VERSION 5.7 ;
BUSBITCHARS "[]" ;
DIVIDERCHAR "/" ;

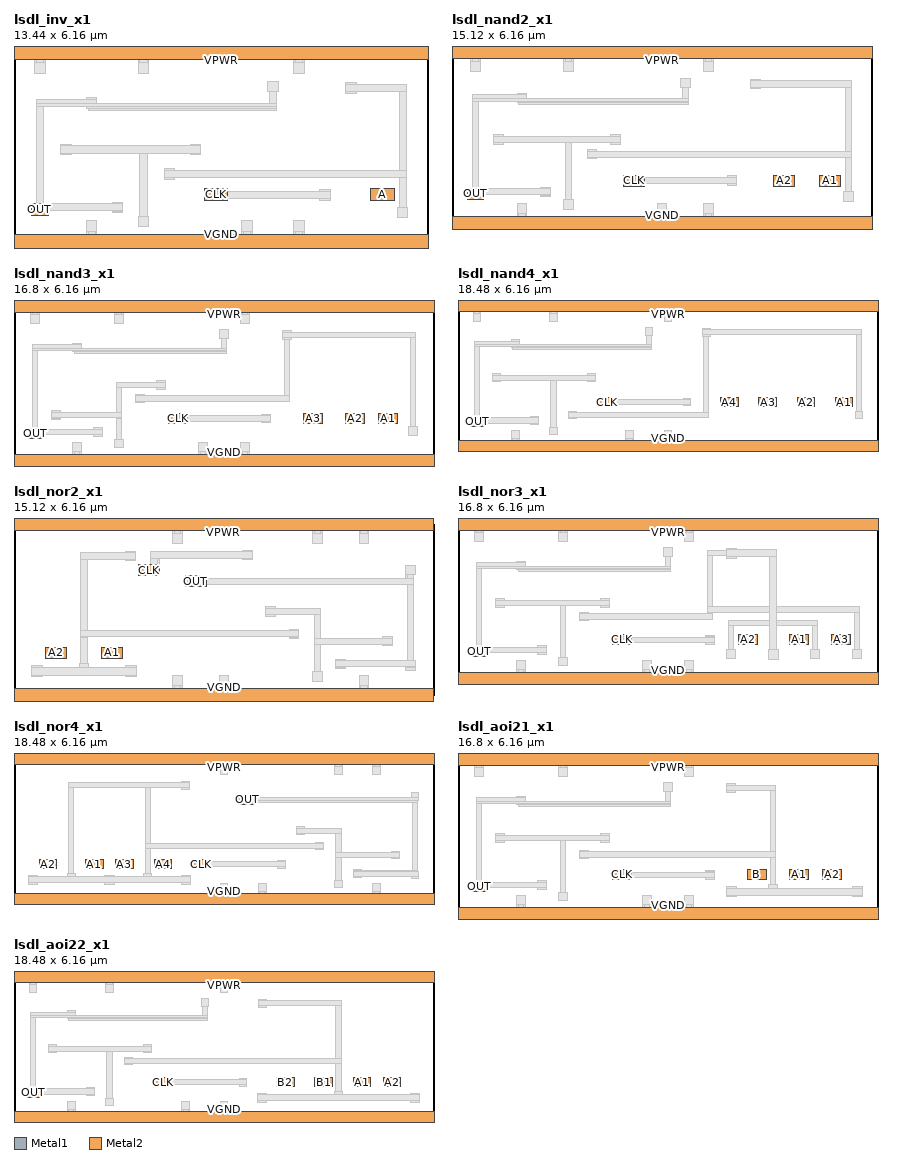
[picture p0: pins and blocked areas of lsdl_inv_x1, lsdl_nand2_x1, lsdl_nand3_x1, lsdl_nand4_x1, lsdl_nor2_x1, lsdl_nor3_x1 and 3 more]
MACRO lsdl_inv_x1
 CLASS CORE ;
 FOREIGN lsdl_inv_x1 0 0 ;
 SIZE 13.44 BY 6.16 ;
 ORIGIN 0 0 ;
 SYMMETRY X Y R90 ;
 SITE unit ;
  PIN VPWR
   DIRECTION INOUT ;
   USE POWER ;
   SHAPE ABUTMENT ;
    PORT
     CLASS CORE ;
       LAYER Metal1 ;
        RECT 0.000 5.920 13.440 6.400 ;
       LAYER Metal2 ;
        RECT 0.000 5.920 13.440 6.400 ;
    END
  END VPWR

  PIN VGND
   DIRECTION INOUT ;
   USE GROUND ;
   SHAPE ABUTMENT ;
    PORT
     CLASS CORE ;
       LAYER Metal1 ;
        RECT 0.000 -0.240 13.440 0.240 ;
       LAYER Metal2 ;
        RECT 0.000 -0.240 13.440 0.240 ;
    END
  END VGND

  PIN OUT
   DIRECTION OUTPUT ;
   USE SIGNAL ;
   SHAPE ABUTMENT ;
    PORT
     CLASS CORE ;
       LAYER Metal2 ;
        RECT 0.560 0.860 1.120 1.260 ;
    END
  END OUT

  PIN CLK
   DIRECTION INPUT ;
   ANTENNAGATEAREA 0.1 ;
   USE SIGNAL ;
   SHAPE ABUTMENT ;
    PORT
     CLASS CORE ;
       LAYER Metal2 ;
        RECT 6.160 1.330 6.920 1.725 ;
    END
  END CLK

  PIN A
   DIRECTION INPUT ;
   ANTENNAGATEAREA 0.1 ;
   USE SIGNAL ;
   SHAPE ABUTMENT ;
    PORT
     CLASS CORE ;
       LAYER Metal2 ;
        RECT 11.560 1.330 12.320 1.725 ;
    END
  END A

 OBS



    LAYER Metal1 ;
     RECT 2.350 0.240 2.405 0.350 ;
     RECT 2.635 0.240 2.690 0.350 ;
     RECT 7.390 0.240 7.445 0.350 ;
     RECT 7.675 0.240 7.730 0.350 ;
     RECT 9.070 0.240 9.125 0.350 ;
     RECT 9.355 0.240 9.410 0.350 ;
     RECT 0.670 5.810 0.725 5.920 ;
     RECT 0.955 5.810 1.010 5.920 ;
     RECT 4.030 5.810 4.085 5.920 ;
     RECT 4.315 5.810 4.370 5.920 ;
     RECT 9.070 5.810 9.125 5.920 ;
     RECT 9.355 5.810 9.410 5.920 ;
     RECT 6.520 1.330 6.920 1.410 ;
     RECT 9.910 1.360 10.250 1.410 ;
     RECT 6.520 1.415 10.250 1.640 ;
     RECT 9.910 1.645 10.250 1.695 ;
     RECT 6.520 1.645 6.920 1.725 ;
     RECT 0.640 0.860 1.040 1.005 ;
     RECT 3.190 0.955 3.530 1.005 ;
     RECT 0.640 1.010 3.530 1.235 ;
     RECT 0.640 1.240 1.040 1.260 ;
     RECT 3.190 1.240 3.530 1.290 ;
     RECT 2.405 4.250 8.515 4.330 ;
     RECT 0.725 1.260 0.955 4.385 ;
     RECT 2.350 4.330 8.515 4.385 ;
     RECT 0.725 4.385 8.515 4.475 ;
     RECT 0.725 4.480 2.690 4.615 ;
     RECT 2.350 4.615 2.690 4.670 ;
     RECT 8.285 4.480 8.515 4.865 ;
     RECT 8.230 4.870 8.570 5.205 ;
     RECT 0.670 5.470 1.010 5.810 ;
     RECT 4.030 5.470 4.370 5.810 ;
     RECT 9.070 5.470 9.410 5.810 ;
     RECT 0.725 5.810 0.955 5.920 ;
     RECT 4.085 5.810 4.315 5.920 ;
     RECT 9.125 5.810 9.355 5.920 ;
     RECT 0.000 5.920 13.440 6.400 ;
     RECT 12.430 0.790 12.770 1.130 ;
     RECT 4.870 2.035 5.210 2.085 ;
     RECT 12.485 1.130 12.715 2.085 ;
     RECT 4.870 2.090 12.715 2.315 ;
     RECT 4.870 2.320 5.210 2.370 ;
     RECT 10.750 4.830 11.090 4.885 ;
     RECT 12.485 2.320 12.715 4.885 ;
     RECT 10.750 4.885 12.715 5.115 ;
     RECT 10.750 5.115 11.090 5.170 ;
     RECT 0.000 -0.240 13.440 0.240 ;
     RECT 2.405 0.240 2.635 0.350 ;
     RECT 7.445 0.240 7.675 0.350 ;
     RECT 9.125 0.240 9.355 0.350 ;
     RECT 2.350 0.350 2.690 0.690 ;
     RECT 7.390 0.350 7.730 0.690 ;
     RECT 9.070 0.350 9.410 0.690 ;
     RECT 11.560 1.330 11.960 1.725 ;
     RECT 4.030 0.490 4.370 0.830 ;
     RECT 1.510 2.830 1.850 2.885 ;
     RECT 4.085 0.830 4.315 2.885 ;
     RECT 5.710 2.830 6.050 2.885 ;
     RECT 1.510 2.885 6.050 3.115 ;
     RECT 1.510 3.115 1.850 3.170 ;
     RECT 5.710 3.115 6.050 3.170 ;

    LAYER Via1 ;
     RECT 6.590 1.400 6.850 1.655 ;
     RECT 0.710 0.930 0.970 1.190 ;
     RECT 0.710 6.030 0.970 6.290 ;
     RECT 2.390 6.030 2.650 6.290 ;
     RECT 4.070 6.030 4.330 6.290 ;
     RECT 5.750 6.030 6.010 6.290 ;
     RECT 7.430 6.030 7.690 6.290 ;
     RECT 9.110 6.030 9.370 6.290 ;
     RECT 10.790 6.030 11.050 6.290 ;
     RECT 12.470 6.030 12.730 6.290 ;
     RECT 0.710 -0.130 0.970 0.130 ;
     RECT 2.390 -0.130 2.650 0.130 ;
     RECT 4.070 -0.130 4.330 0.130 ;
     RECT 5.750 -0.130 6.010 0.130 ;
     RECT 7.430 -0.130 7.690 0.130 ;
     RECT 9.110 -0.130 9.370 0.130 ;
     RECT 10.790 -0.130 11.050 0.130 ;
     RECT 12.470 -0.130 12.730 0.130 ;
     RECT 11.630 1.400 11.890 1.655 ;

    LAYER Metal2 ;
     RECT 6.520 1.330 6.920 1.725 ;
     RECT 0.640 0.860 1.040 1.260 ;
     RECT 0.000 5.920 13.440 6.400 ;
     RECT 0.000 -0.240 13.440 0.240 ;
     RECT 11.560 1.330 11.960 1.725 ;

 END
END lsdl_inv_x1

MACRO lsdl_nand2_x1
 CLASS CORE ;
 FOREIGN lsdl_nand2_x1 0 0 ;
 SIZE 15.120000000000001 BY 6.16 ;
 ORIGIN 0 0 ;
 SYMMETRY X Y R90 ;
 SITE unit ;
  PIN VPWR
   DIRECTION INOUT ;
   USE POWER ;
   SHAPE ABUTMENT ;
    PORT
     CLASS CORE ;
       LAYER Metal1 ;
        RECT 0.000 5.920 15.120 6.400 ;
       LAYER Metal2 ;
        RECT 0.000 5.920 15.120 6.400 ;
    END
  END VPWR

  PIN VGND
   DIRECTION INOUT ;
   USE GROUND ;
   SHAPE ABUTMENT ;
    PORT
     CLASS CORE ;
       LAYER Metal1 ;
        RECT 0.000 -0.240 15.120 0.240 ;
       LAYER Metal2 ;
        RECT 0.000 -0.240 15.120 0.240 ;
    END
  END VGND

  PIN OUT
   DIRECTION OUTPUT ;
   USE SIGNAL ;
   SHAPE ABUTMENT ;
    PORT
     CLASS CORE ;
       LAYER Metal2 ;
        RECT 0.560 0.860 1.120 1.260 ;
    END
  END OUT

  PIN CLK
   DIRECTION INPUT ;
   ANTENNAGATEAREA 0.1 ;
   USE SIGNAL ;
   SHAPE ABUTMENT ;
    PORT
     CLASS CORE ;
       LAYER Metal2 ;
        RECT 6.160 1.330 6.920 1.725 ;
    END
  END CLK

  PIN A2
   DIRECTION INPUT ;
   ANTENNAGATEAREA 0.1 ;
   USE SIGNAL ;
   SHAPE ABUTMENT ;
    PORT
     CLASS CORE ;
       LAYER Metal2 ;
        RECT 11.560 1.330 12.320 1.725 ;
    END
  END A2

  PIN A1
   DIRECTION INPUT ;
   ANTENNAGATEAREA 0.1 ;
   USE SIGNAL ;
   SHAPE ABUTMENT ;
    PORT
     CLASS CORE ;
       LAYER Metal2 ;
        RECT 13.240 1.330 14.000 1.725 ;
    END
  END A1

 OBS



    LAYER Metal1 ;
     RECT 2.350 0.240 2.405 0.350 ;
     RECT 2.635 0.240 2.690 0.350 ;
     RECT 7.390 0.240 7.445 0.350 ;
     RECT 7.675 0.240 7.730 0.350 ;
     RECT 9.070 0.240 9.125 0.350 ;
     RECT 9.355 0.240 9.410 0.350 ;
     RECT 0.670 5.810 0.725 5.920 ;
     RECT 0.955 5.810 1.010 5.920 ;
     RECT 4.030 5.810 4.085 5.920 ;
     RECT 4.315 5.810 4.370 5.920 ;
     RECT 9.070 5.810 9.125 5.920 ;
     RECT 9.355 5.810 9.410 5.920 ;
     RECT 6.520 1.330 6.920 1.410 ;
     RECT 9.910 1.360 10.250 1.410 ;
     RECT 6.520 1.415 10.250 1.640 ;
     RECT 9.910 1.645 10.250 1.695 ;
     RECT 6.520 1.645 6.920 1.725 ;
     RECT 11.560 1.330 11.960 1.725 ;
     RECT 0.640 0.860 1.040 1.005 ;
     RECT 3.190 0.955 3.530 1.005 ;
     RECT 0.640 1.010 3.530 1.235 ;
     RECT 0.640 1.240 1.040 1.260 ;
     RECT 3.190 1.240 3.530 1.290 ;
     RECT 2.405 4.250 8.515 4.330 ;
     RECT 0.725 1.260 0.955 4.385 ;
     RECT 2.350 4.330 8.515 4.385 ;
     RECT 0.725 4.385 8.515 4.475 ;
     RECT 0.725 4.480 2.690 4.615 ;
     RECT 2.350 4.615 2.690 4.670 ;
     RECT 8.285 4.480 8.515 4.865 ;
     RECT 8.230 4.870 8.570 5.205 ;
     RECT 0.670 5.470 1.010 5.810 ;
     RECT 4.030 5.470 4.370 5.810 ;
     RECT 9.070 5.470 9.410 5.810 ;
     RECT 0.725 5.810 0.955 5.920 ;
     RECT 4.085 5.810 4.315 5.920 ;
     RECT 9.125 5.810 9.355 5.920 ;
     RECT 0.000 5.920 15.120 6.400 ;
     RECT 14.110 0.790 14.450 1.130 ;
     RECT 4.870 2.305 5.210 2.355 ;
     RECT 14.165 1.130 14.395 2.355 ;
     RECT 4.870 2.360 14.395 2.585 ;
     RECT 4.870 2.590 5.210 2.640 ;
     RECT 10.750 4.830 11.090 4.885 ;
     RECT 14.165 2.590 14.395 4.885 ;
     RECT 10.750 4.885 14.395 5.115 ;
     RECT 10.750 5.115 11.090 5.170 ;
     RECT 13.240 1.330 13.640 1.725 ;
     RECT 0.000 -0.240 15.120 0.240 ;
     RECT 2.405 0.240 2.635 0.350 ;
     RECT 7.445 0.240 7.675 0.350 ;
     RECT 9.125 0.240 9.355 0.350 ;
     RECT 2.350 0.350 2.690 0.690 ;
     RECT 7.390 0.350 7.730 0.690 ;
     RECT 9.070 0.350 9.410 0.690 ;
     RECT 4.030 0.490 4.370 0.830 ;
     RECT 1.510 2.830 1.850 2.885 ;
     RECT 4.085 0.830 4.315 2.885 ;
     RECT 5.710 2.830 6.050 2.885 ;
     RECT 1.510 2.885 6.050 3.115 ;
     RECT 1.510 3.115 1.850 3.170 ;
     RECT 5.710 3.115 6.050 3.170 ;

    LAYER Via1 ;
     RECT 6.590 1.400 6.850 1.655 ;
     RECT 11.630 1.400 11.890 1.655 ;
     RECT 0.710 0.930 0.970 1.190 ;
     RECT 0.710 6.030 0.970 6.290 ;
     RECT 2.390 6.030 2.650 6.290 ;
     RECT 4.070 6.030 4.330 6.290 ;
     RECT 5.750 6.030 6.010 6.290 ;
     RECT 7.430 6.030 7.690 6.290 ;
     RECT 9.110 6.030 9.370 6.290 ;
     RECT 10.790 6.030 11.050 6.290 ;
     RECT 12.470 6.030 12.730 6.290 ;
     RECT 14.150 6.030 14.410 6.290 ;
     RECT 13.310 1.400 13.570 1.655 ;
     RECT 0.710 -0.130 0.970 0.130 ;
     RECT 2.390 -0.130 2.650 0.130 ;
     RECT 4.070 -0.130 4.330 0.130 ;
     RECT 5.750 -0.130 6.010 0.130 ;
     RECT 7.430 -0.130 7.690 0.130 ;
     RECT 9.110 -0.130 9.370 0.130 ;
     RECT 10.790 -0.130 11.050 0.130 ;
     RECT 12.470 -0.130 12.730 0.130 ;
     RECT 14.150 -0.130 14.410 0.130 ;

    LAYER Metal2 ;
     RECT 6.520 1.330 6.920 1.725 ;
     RECT 11.560 1.330 11.960 1.725 ;
     RECT 0.640 0.860 1.040 1.260 ;
     RECT 0.000 5.920 15.120 6.400 ;
     RECT 13.240 1.330 13.640 1.725 ;
     RECT 0.000 -0.240 15.120 0.240 ;

 END
END lsdl_nand2_x1

MACRO lsdl_nand3_x1
 CLASS CORE ;
 FOREIGN lsdl_nand3_x1 0 0 ;
 SIZE 16.8 BY 6.16 ;
 ORIGIN 0 0 ;
 SYMMETRY X Y R90 ;
 SITE unit ;
  PIN VPWR
   DIRECTION INOUT ;
   USE POWER ;
   SHAPE ABUTMENT ;
    PORT
     CLASS CORE ;
       LAYER Metal1 ;
        RECT 0.000 5.920 16.800 6.400 ;
       LAYER Metal2 ;
        RECT 0.000 5.920 16.800 6.400 ;
    END
  END VPWR

  PIN VGND
   DIRECTION INOUT ;
   USE GROUND ;
   SHAPE ABUTMENT ;
    PORT
     CLASS CORE ;
       LAYER Metal1 ;
        RECT 0.000 -0.240 16.800 0.240 ;
       LAYER Metal2 ;
        RECT 0.000 -0.240 16.800 0.240 ;
    END
  END VGND

  PIN OUT
   DIRECTION OUTPUT ;
   USE SIGNAL ;
   SHAPE ABUTMENT ;
    PORT
     CLASS CORE ;
       LAYER Metal2 ;
        RECT 0.560 0.860 1.120 1.260 ;
    END
  END OUT

  PIN CLK
   DIRECTION INPUT ;
   ANTENNAGATEAREA 0.1 ;
   USE SIGNAL ;
   SHAPE ABUTMENT ;
    PORT
     CLASS CORE ;
       LAYER Metal2 ;
        RECT 6.160 1.465 6.920 1.860 ;
    END
  END CLK

  PIN A1
   DIRECTION INPUT ;
   ANTENNAGATEAREA 0.1 ;
   USE SIGNAL ;
   SHAPE ABUTMENT ;
    PORT
     CLASS CORE ;
       LAYER Metal2 ;
        RECT 14.560 1.465 15.320 1.860 ;
    END
  END A1

  PIN A3
   DIRECTION INPUT ;
   ANTENNAGATEAREA 0.1 ;
   USE SIGNAL ;
   SHAPE ABUTMENT ;
    PORT
     CLASS CORE ;
       LAYER Metal2 ;
        RECT 11.560 1.465 12.320 1.860 ;
    END
  END A3

  PIN A2
   DIRECTION INPUT ;
   ANTENNAGATEAREA 0.1 ;
   USE SIGNAL ;
   SHAPE ABUTMENT ;
    PORT
     CLASS CORE ;
       LAYER Metal2 ;
        RECT 13.240 1.465 14.000 1.860 ;
    END
  END A2

 OBS



    LAYER Metal1 ;
     RECT 2.350 0.240 2.405 0.350 ;
     RECT 2.635 0.240 2.690 0.350 ;
     RECT 7.390 0.240 7.445 0.350 ;
     RECT 7.675 0.240 7.730 0.350 ;
     RECT 9.070 0.240 9.125 0.350 ;
     RECT 9.355 0.240 9.410 0.350 ;
     RECT 0.670 5.810 0.725 5.920 ;
     RECT 0.955 5.810 1.010 5.920 ;
     RECT 4.030 5.810 4.085 5.920 ;
     RECT 4.315 5.810 4.370 5.920 ;
     RECT 9.070 5.810 9.125 5.920 ;
     RECT 9.355 5.810 9.410 5.920 ;
     RECT 6.520 1.465 6.920 1.545 ;
     RECT 9.910 1.495 10.250 1.545 ;
     RECT 6.520 1.550 10.250 1.775 ;
     RECT 9.910 1.780 10.250 1.830 ;
     RECT 6.520 1.780 6.920 1.860 ;
     RECT 13.240 1.465 13.640 1.860 ;
     RECT 0.640 0.860 1.040 1.005 ;
     RECT 3.190 0.955 3.530 1.005 ;
     RECT 0.640 1.010 3.530 1.235 ;
     RECT 0.640 1.240 1.040 1.260 ;
     RECT 3.190 1.240 3.530 1.290 ;
     RECT 2.405 4.250 8.515 4.330 ;
     RECT 0.725 1.260 0.955 4.385 ;
     RECT 2.350 4.330 8.515 4.385 ;
     RECT 0.725 4.385 8.515 4.475 ;
     RECT 0.725 4.480 2.690 4.615 ;
     RECT 2.350 4.615 2.690 4.670 ;
     RECT 8.285 4.480 8.515 4.865 ;
     RECT 8.230 4.870 8.570 5.205 ;
     RECT 0.670 5.470 1.010 5.810 ;
     RECT 4.030 5.470 4.370 5.810 ;
     RECT 9.070 5.470 9.410 5.810 ;
     RECT 0.725 5.810 0.955 5.920 ;
     RECT 4.085 5.810 4.315 5.920 ;
     RECT 9.125 5.810 9.355 5.920 ;
     RECT 0.000 5.920 16.800 6.400 ;
     RECT 15.790 0.990 16.130 1.330 ;
     RECT 4.870 2.305 5.210 2.355 ;
     RECT 4.870 2.360 11.035 2.585 ;
     RECT 4.870 2.590 5.210 2.640 ;
     RECT 10.805 2.590 11.035 4.830 ;
     RECT 10.750 4.830 11.090 4.885 ;
     RECT 15.845 1.330 16.075 4.885 ;
     RECT 10.750 4.885 16.075 5.115 ;
     RECT 10.750 5.115 11.090 5.170 ;
     RECT 14.920 1.465 15.320 1.860 ;
     RECT 0.000 -0.240 16.800 0.240 ;
     RECT 2.405 0.240 2.635 0.350 ;
     RECT 7.445 0.240 7.675 0.350 ;
     RECT 9.125 0.240 9.355 0.350 ;
     RECT 2.350 0.350 2.690 0.690 ;
     RECT 7.390 0.350 7.730 0.690 ;
     RECT 9.070 0.350 9.410 0.690 ;
     RECT 11.560 1.465 11.960 1.860 ;
     RECT 4.030 0.490 4.370 0.830 ;
     RECT 1.510 1.630 1.850 1.680 ;
     RECT 4.085 0.830 4.315 1.680 ;
     RECT 1.510 1.685 4.315 1.910 ;
     RECT 1.510 1.915 1.850 1.965 ;
     RECT 4.085 1.915 4.315 2.885 ;
     RECT 5.710 2.830 6.050 2.885 ;
     RECT 4.085 2.885 6.050 3.115 ;
     RECT 5.710 3.115 6.050 3.170 ;

    LAYER Via1 ;
     RECT 6.590 1.535 6.850 1.790 ;
     RECT 13.310 1.535 13.570 1.790 ;
     RECT 0.710 0.930 0.970 1.190 ;
     RECT 0.710 6.030 0.970 6.290 ;
     RECT 2.390 6.030 2.650 6.290 ;
     RECT 4.070 6.030 4.330 6.290 ;
     RECT 5.750 6.030 6.010 6.290 ;
     RECT 7.430 6.030 7.690 6.290 ;
     RECT 9.110 6.030 9.370 6.290 ;
     RECT 10.790 6.030 11.050 6.290 ;
     RECT 12.470 6.030 12.730 6.290 ;
     RECT 14.150 6.030 14.410 6.290 ;
     RECT 15.830 6.030 16.090 6.290 ;
     RECT 14.990 1.535 15.250 1.790 ;
     RECT 0.710 -0.130 0.970 0.130 ;
     RECT 2.390 -0.130 2.650 0.130 ;
     RECT 4.070 -0.130 4.330 0.130 ;
     RECT 5.750 -0.130 6.010 0.130 ;
     RECT 7.430 -0.130 7.690 0.130 ;
     RECT 9.110 -0.130 9.370 0.130 ;
     RECT 10.790 -0.130 11.050 0.130 ;
     RECT 12.470 -0.130 12.730 0.130 ;
     RECT 14.150 -0.130 14.410 0.130 ;
     RECT 15.830 -0.130 16.090 0.130 ;
     RECT 11.630 1.535 11.890 1.790 ;

    LAYER Metal2 ;
     RECT 6.520 1.465 6.920 1.860 ;
     RECT 13.240 1.465 13.640 1.860 ;
     RECT 0.640 0.860 1.040 1.260 ;
     RECT 0.000 5.920 16.800 6.400 ;
     RECT 14.920 1.465 15.320 1.860 ;
     RECT 0.000 -0.240 16.800 0.240 ;
     RECT 11.560 1.465 11.960 1.860 ;

 END
END lsdl_nand3_x1

MACRO lsdl_nand4_x1
 CLASS CORE ;
 FOREIGN lsdl_nand4_x1 0 0 ;
 SIZE 18.48 BY 6.16 ;
 ORIGIN 0 0 ;
 SYMMETRY X Y R90 ;
 SITE unit ;
  PIN VPWR
   DIRECTION INOUT ;
   USE POWER ;
   SHAPE ABUTMENT ;
    PORT
     CLASS CORE ;
       LAYER Metal1 ;
        RECT 0.000 5.920 18.480 6.400 ;
       LAYER Metal2 ;
        RECT 0.000 5.920 18.480 6.400 ;
    END
  END VPWR

  PIN VGND
   DIRECTION INOUT ;
   USE GROUND ;
   SHAPE ABUTMENT ;
    PORT
     CLASS CORE ;
       LAYER Metal1 ;
        RECT 0.000 -0.240 18.480 0.240 ;
       LAYER Metal2 ;
        RECT 0.000 -0.240 18.480 0.240 ;
    END
  END VGND

  PIN OUT
   DIRECTION OUTPUT ;
   USE SIGNAL ;
   SHAPE ABUTMENT ;
    PORT
     CLASS CORE ;
       LAYER Metal2 ;
        RECT 0.560 0.860 1.120 1.260 ;
    END
  END OUT

  PIN A4
   DIRECTION INPUT ;
   ANTENNAGATEAREA 0.1 ;
   USE SIGNAL ;
   SHAPE ABUTMENT ;
    PORT
     CLASS CORE ;
       LAYER Metal2 ;
        RECT 11.560 1.735 12.320 2.130 ;
    END
  END A4

  PIN A2
   DIRECTION INPUT ;
   ANTENNAGATEAREA 0.1 ;
   USE SIGNAL ;
   SHAPE ABUTMENT ;
    PORT
     CLASS CORE ;
       LAYER Metal2 ;
        RECT 14.920 1.735 15.680 2.130 ;
    END
  END A2

  PIN CLK
   DIRECTION INPUT ;
   ANTENNAGATEAREA 0.1 ;
   USE SIGNAL ;
   SHAPE ABUTMENT ;
    PORT
     CLASS CORE ;
       LAYER Metal2 ;
        RECT 6.160 1.735 6.920 2.130 ;
    END
  END CLK

  PIN A1
   DIRECTION INPUT ;
   ANTENNAGATEAREA 0.1 ;
   USE SIGNAL ;
   SHAPE ABUTMENT ;
    PORT
     CLASS CORE ;
       LAYER Metal2 ;
        RECT 16.600 1.735 17.360 2.130 ;
    END
  END A1

  PIN A3
   DIRECTION INPUT ;
   ANTENNAGATEAREA 0.1 ;
   USE SIGNAL ;
   SHAPE ABUTMENT ;
    PORT
     CLASS CORE ;
       LAYER Metal2 ;
        RECT 13.240 1.735 14.000 2.130 ;
    END
  END A3

 OBS



    LAYER Metal1 ;
     RECT 2.350 0.240 2.405 0.350 ;
     RECT 2.635 0.240 2.690 0.350 ;
     RECT 7.390 0.240 7.445 0.350 ;
     RECT 7.675 0.240 7.730 0.350 ;
     RECT 9.070 0.240 9.125 0.350 ;
     RECT 9.355 0.240 9.410 0.350 ;
     RECT 0.670 5.810 0.725 5.920 ;
     RECT 0.955 5.810 1.010 5.920 ;
     RECT 4.030 5.810 4.085 5.920 ;
     RECT 4.315 5.810 4.370 5.920 ;
     RECT 9.070 5.810 9.125 5.920 ;
     RECT 9.355 5.810 9.410 5.920 ;
     RECT 6.520 1.735 6.920 1.815 ;
     RECT 9.910 1.765 10.250 1.815 ;
     RECT 6.520 1.820 10.250 2.045 ;
     RECT 9.910 2.050 10.250 2.100 ;
     RECT 6.520 2.050 6.920 2.130 ;
     RECT 14.920 1.735 15.320 2.130 ;
     RECT 0.640 0.860 1.040 1.005 ;
     RECT 3.190 0.955 3.530 1.005 ;
     RECT 0.640 1.010 3.530 1.235 ;
     RECT 0.640 1.240 1.040 1.260 ;
     RECT 3.190 1.240 3.530 1.290 ;
     RECT 2.405 4.250 8.515 4.330 ;
     RECT 0.725 1.260 0.955 4.385 ;
     RECT 2.350 4.330 8.515 4.385 ;
     RECT 0.725 4.385 8.515 4.475 ;
     RECT 0.725 4.480 2.690 4.615 ;
     RECT 2.350 4.615 2.690 4.670 ;
     RECT 8.285 4.480 8.515 4.865 ;
     RECT 8.230 4.870 8.570 5.205 ;
     RECT 0.670 5.470 1.010 5.810 ;
     RECT 4.030 5.470 4.370 5.810 ;
     RECT 9.070 5.470 9.410 5.810 ;
     RECT 0.725 5.810 0.955 5.920 ;
     RECT 4.085 5.810 4.315 5.920 ;
     RECT 9.125 5.810 9.355 5.920 ;
     RECT 0.000 5.920 18.480 6.400 ;
     RECT 4.870 1.190 5.210 1.245 ;
     RECT 4.870 1.245 11.035 1.475 ;
     RECT 4.870 1.475 5.210 1.530 ;
     RECT 17.470 1.190 17.810 1.530 ;
     RECT 10.805 1.475 11.035 4.830 ;
     RECT 10.750 4.830 11.090 4.885 ;
     RECT 17.525 1.530 17.755 4.885 ;
     RECT 10.750 4.885 17.755 5.115 ;
     RECT 10.750 5.115 11.090 5.170 ;
     RECT 16.600 1.735 17.000 2.130 ;
     RECT 0.000 -0.240 18.480 0.240 ;
     RECT 2.405 0.240 2.635 0.350 ;
     RECT 7.445 0.240 7.675 0.350 ;
     RECT 9.125 0.240 9.355 0.350 ;
     RECT 2.350 0.350 2.690 0.690 ;
     RECT 7.390 0.350 7.730 0.690 ;
     RECT 9.070 0.350 9.410 0.690 ;
     RECT 11.560 1.735 11.960 2.130 ;
     RECT 13.240 1.735 13.640 2.130 ;
     RECT 4.030 0.490 4.370 0.830 ;
     RECT 1.510 2.830 1.850 2.885 ;
     RECT 4.085 0.830 4.315 2.885 ;
     RECT 5.710 2.830 6.050 2.885 ;
     RECT 1.510 2.885 6.050 3.115 ;
     RECT 1.510 3.115 1.850 3.170 ;
     RECT 5.710 3.115 6.050 3.170 ;

    LAYER Via1 ;
     RECT 6.590 1.805 6.850 2.060 ;
     RECT 14.990 1.805 15.250 2.060 ;
     RECT 0.710 0.930 0.970 1.190 ;
     RECT 0.710 6.030 0.970 6.290 ;
     RECT 2.390 6.030 2.650 6.290 ;
     RECT 4.070 6.030 4.330 6.290 ;
     RECT 5.750 6.030 6.010 6.290 ;
     RECT 7.430 6.030 7.690 6.290 ;
     RECT 9.110 6.030 9.370 6.290 ;
     RECT 10.790 6.030 11.050 6.290 ;
     RECT 12.470 6.030 12.730 6.290 ;
     RECT 14.150 6.030 14.410 6.290 ;
     RECT 15.830 6.030 16.090 6.290 ;
     RECT 17.510 6.030 17.770 6.290 ;
     RECT 16.670 1.805 16.930 2.060 ;
     RECT 0.710 -0.130 0.970 0.130 ;
     RECT 2.390 -0.130 2.650 0.130 ;
     RECT 4.070 -0.130 4.330 0.130 ;
     RECT 5.750 -0.130 6.010 0.130 ;
     RECT 7.430 -0.130 7.690 0.130 ;
     RECT 9.110 -0.130 9.370 0.130 ;
     RECT 10.790 -0.130 11.050 0.130 ;
     RECT 12.470 -0.130 12.730 0.130 ;
     RECT 14.150 -0.130 14.410 0.130 ;
     RECT 15.830 -0.130 16.090 0.130 ;
     RECT 17.510 -0.130 17.770 0.130 ;
     RECT 11.630 1.805 11.890 2.060 ;
     RECT 13.310 1.805 13.570 2.060 ;

    LAYER Metal2 ;
     RECT 6.520 1.735 6.920 2.130 ;
     RECT 14.920 1.735 15.320 2.130 ;
     RECT 0.640 0.860 1.040 1.260 ;
     RECT 0.000 5.920 18.480 6.400 ;
     RECT 16.600 1.735 17.000 2.130 ;
     RECT 0.000 -0.240 18.480 0.240 ;
     RECT 11.560 1.735 11.960 2.130 ;
     RECT 13.240 1.735 13.640 2.130 ;

 END
END lsdl_nand4_x1

MACRO lsdl_nor2_x1
 CLASS CORE ;
 FOREIGN lsdl_nor2_x1 0 0 ;
 SIZE 15.120000000000001 BY 6.16 ;
 ORIGIN 0 0 ;
 SYMMETRY X Y R90 ;
 SITE unit ;
  PIN VPWR
   DIRECTION INOUT ;
   USE POWER ;
   SHAPE ABUTMENT ;
    PORT
     CLASS CORE ;
       LAYER Metal1 ;
        RECT 0.000 5.920 15.120 6.400 ;
       LAYER Metal2 ;
        RECT 0.000 5.920 15.120 6.400 ;
    END
  END VPWR

  PIN VGND
   DIRECTION INOUT ;
   USE GROUND ;
   SHAPE ABUTMENT ;
    PORT
     CLASS CORE ;
       LAYER Metal1 ;
        RECT 0.000 -0.240 15.120 0.240 ;
       LAYER Metal2 ;
        RECT 0.000 -0.240 15.120 0.240 ;
    END
  END VGND

  PIN OUT
   DIRECTION OUTPUT ;
   USE SIGNAL ;
   SHAPE ABUTMENT ;
    PORT
     CLASS CORE ;
       LAYER Metal2 ;
        RECT 6.160 3.895 6.920 4.290 ;
    END
  END OUT

  PIN A1
   DIRECTION INPUT ;
   ANTENNAGATEAREA 0.1 ;
   USE SIGNAL ;
   SHAPE ABUTMENT ;
    PORT
     CLASS CORE ;
       LAYER Metal2 ;
        RECT 3.160 1.330 3.920 1.725 ;
    END
  END A1

  PIN CLK
   DIRECTION INPUT ;
   ANTENNAGATEAREA 0.1 ;
   USE SIGNAL ;
   SHAPE ABUTMENT ;
    PORT
     CLASS CORE ;
       LAYER Metal2 ;
        RECT 4.480 4.300 5.240 4.700 ;
    END
  END CLK

  PIN A2
   DIRECTION INPUT ;
   ANTENNAGATEAREA 0.1 ;
   USE SIGNAL ;
   SHAPE ABUTMENT ;
    PORT
     CLASS CORE ;
       LAYER Metal2 ;
        RECT 1.120 1.330 1.880 1.725 ;
    END
  END A2

 OBS



    LAYER Metal1 ;
     RECT 5.710 0.240 5.765 0.350 ;
     RECT 5.995 0.240 6.050 0.350 ;
     RECT 7.390 0.240 7.445 0.350 ;
     RECT 7.675 0.240 7.730 0.350 ;
     RECT 12.430 0.240 12.485 0.350 ;
     RECT 12.715 0.240 12.770 0.350 ;
     RECT 14.110 4.210 14.165 4.330 ;
     RECT 5.155 4.700 5.240 4.920 ;
     RECT 5.710 5.810 5.765 5.920 ;
     RECT 5.995 5.810 6.050 5.920 ;
     RECT 10.750 5.810 10.805 5.920 ;
     RECT 11.035 5.810 11.090 5.920 ;
     RECT 12.430 5.810 12.485 5.920 ;
     RECT 12.715 5.810 12.770 5.920 ;
     RECT 4.840 4.300 5.240 4.700 ;
     RECT 4.925 4.700 5.155 4.920 ;
     RECT 8.230 4.870 8.570 4.920 ;
     RECT 4.925 4.925 8.570 5.150 ;
     RECT 8.230 5.155 8.570 5.205 ;
     RECT 1.480 1.330 1.880 1.725 ;
     RECT 11.590 0.955 11.930 1.005 ;
     RECT 14.110 0.890 14.450 1.005 ;
     RECT 11.590 1.010 14.450 1.230 ;
     RECT 11.590 1.230 14.395 1.235 ;
     RECT 11.590 1.240 11.930 1.290 ;
     RECT 6.520 3.895 6.920 3.975 ;
     RECT 14.165 1.240 14.395 3.975 ;
     RECT 6.520 3.980 14.395 4.205 ;
     RECT 6.520 4.210 6.920 4.290 ;
     RECT 14.165 4.210 14.395 4.330 ;
     RECT 14.110 4.330 14.450 4.670 ;
     RECT 5.710 5.470 6.050 5.810 ;
     RECT 10.750 5.470 11.090 5.810 ;
     RECT 12.430 5.470 12.770 5.810 ;
     RECT 5.765 5.810 5.995 5.920 ;
     RECT 10.805 5.810 11.035 5.920 ;
     RECT 12.485 5.810 12.715 5.920 ;
     RECT 0.000 5.920 15.120 6.400 ;
     RECT 2.350 0.790 2.690 1.130 ;
     RECT 2.405 1.130 2.635 2.085 ;
     RECT 9.910 2.035 10.250 2.085 ;
     RECT 2.405 2.090 10.250 2.315 ;
     RECT 9.910 2.320 10.250 2.370 ;
     RECT 2.405 2.320 2.635 4.885 ;
     RECT 4.030 4.830 4.370 4.885 ;
     RECT 2.405 4.885 4.370 5.115 ;
     RECT 4.030 5.115 4.370 5.170 ;
     RECT 3.160 1.330 3.560 1.725 ;
     RECT 0.640 0.655 1.040 1.050 ;
     RECT 4.000 0.655 4.400 1.050 ;
     RECT 0.000 -0.240 15.120 0.240 ;
     RECT 5.765 0.240 5.995 0.350 ;
     RECT 7.445 0.240 7.675 0.350 ;
     RECT 12.485 0.240 12.715 0.350 ;
     RECT 5.710 0.350 6.050 0.690 ;
     RECT 7.390 0.350 7.730 0.690 ;
     RECT 12.430 0.350 12.770 0.690 ;
     RECT 10.750 0.490 11.090 0.830 ;
     RECT 10.805 0.830 11.035 1.815 ;
     RECT 13.270 1.765 13.610 1.815 ;
     RECT 10.805 1.820 13.610 2.045 ;
     RECT 13.270 2.050 13.610 2.100 ;
     RECT 9.070 2.830 9.410 2.885 ;
     RECT 10.805 2.050 11.035 2.885 ;
     RECT 9.070 2.885 11.035 3.115 ;
     RECT 9.070 3.115 9.410 3.170 ;

    LAYER Via1 ;
     RECT 4.910 4.370 5.170 4.630 ;
     RECT 1.550 1.400 1.810 1.655 ;
     RECT 6.590 3.965 6.850 4.220 ;
     RECT 0.710 6.030 0.970 6.290 ;
     RECT 2.390 6.030 2.650 6.290 ;
     RECT 4.070 6.030 4.330 6.290 ;
     RECT 5.750 6.030 6.010 6.290 ;
     RECT 7.430 6.030 7.690 6.290 ;
     RECT 9.110 6.030 9.370 6.290 ;
     RECT 10.790 6.030 11.050 6.290 ;
     RECT 12.470 6.030 12.730 6.290 ;
     RECT 14.150 6.030 14.410 6.290 ;
     RECT 3.230 1.400 3.490 1.655 ;
     RECT 0.710 0.725 0.970 0.980 ;
     RECT 4.070 0.725 4.330 0.980 ;
     RECT 0.710 -0.130 0.970 0.130 ;
     RECT 2.390 -0.130 2.650 0.130 ;
     RECT 4.070 -0.130 4.330 0.130 ;
     RECT 5.750 -0.130 6.010 0.130 ;
     RECT 7.430 -0.130 7.690 0.130 ;
     RECT 9.110 -0.130 9.370 0.130 ;
     RECT 10.790 -0.130 11.050 0.130 ;
     RECT 12.470 -0.130 12.730 0.130 ;
     RECT 14.150 -0.130 14.410 0.130 ;

    LAYER Metal2 ;
     RECT 4.840 4.300 5.240 4.700 ;
     RECT 1.480 1.330 1.880 1.725 ;
     RECT 6.520 3.895 6.920 4.290 ;
     RECT 0.000 5.920 15.120 6.400 ;
     RECT 3.160 1.330 3.560 1.725 ;
     RECT 0.640 0.655 1.040 0.710 ;
     RECT 4.000 0.655 4.400 0.710 ;
     RECT 0.640 0.715 4.400 0.990 ;
     RECT 0.640 0.995 1.040 1.050 ;
     RECT 4.000 0.995 4.400 1.050 ;
     RECT 0.000 -0.240 15.120 0.240 ;

 END
END lsdl_nor2_x1

MACRO lsdl_nor3_x1
 CLASS CORE ;
 FOREIGN lsdl_nor3_x1 0 0 ;
 SIZE 16.8 BY 6.16 ;
 ORIGIN 0 0 ;
 SYMMETRY X Y R90 ;
 SITE unit ;
  PIN VPWR
   DIRECTION INOUT ;
   USE POWER ;
   SHAPE ABUTMENT ;
    PORT
     CLASS CORE ;
       LAYER Metal1 ;
        RECT 0.000 5.920 16.800 6.400 ;
       LAYER Metal2 ;
        RECT 0.000 5.920 16.800 6.400 ;
    END
  END VPWR

  PIN VGND
   DIRECTION INOUT ;
   USE GROUND ;
   SHAPE ABUTMENT ;
    PORT
     CLASS CORE ;
       LAYER Metal1 ;
        RECT 0.000 -0.240 16.800 0.240 ;
       LAYER Metal2 ;
        RECT 0.000 -0.240 16.800 0.240 ;
    END
  END VGND

  PIN OUT
   DIRECTION OUTPUT ;
   USE SIGNAL ;
   SHAPE ABUTMENT ;
    PORT
     CLASS CORE ;
       LAYER Metal2 ;
        RECT 0.560 0.860 1.120 1.260 ;
    END
  END OUT

  PIN A2
   DIRECTION INPUT ;
   ANTENNAGATEAREA 0.1 ;
   USE SIGNAL ;
   SHAPE ABUTMENT ;
    PORT
     CLASS CORE ;
       LAYER Metal2 ;
        RECT 11.200 1.330 11.960 1.725 ;
    END
  END A2

  PIN A3
   DIRECTION INPUT ;
   ANTENNAGATEAREA 0.1 ;
   USE SIGNAL ;
   SHAPE ABUTMENT ;
    PORT
     CLASS CORE ;
       LAYER Metal2 ;
        RECT 14.920 1.330 15.680 1.725 ;
    END
  END A3

  PIN CLK
   DIRECTION INPUT ;
   ANTENNAGATEAREA 0.1 ;
   USE SIGNAL ;
   SHAPE ABUTMENT ;
    PORT
     CLASS CORE ;
       LAYER Metal2 ;
        RECT 6.160 1.330 6.920 1.725 ;
    END
  END CLK

  PIN A1
   DIRECTION INPUT ;
   ANTENNAGATEAREA 0.1 ;
   USE SIGNAL ;
   SHAPE ABUTMENT ;
    PORT
     CLASS CORE ;
       LAYER Metal2 ;
        RECT 13.240 1.330 14.000 1.725 ;
    END
  END A1

 OBS



    LAYER Metal1 ;
     RECT 2.350 0.240 2.405 0.350 ;
     RECT 2.635 0.240 2.690 0.350 ;
     RECT 7.390 0.240 7.445 0.350 ;
     RECT 7.675 0.240 7.730 0.350 ;
     RECT 9.070 0.240 9.125 0.350 ;
     RECT 9.355 0.240 9.410 0.350 ;
     RECT 0.670 5.810 0.725 5.920 ;
     RECT 0.955 5.810 1.010 5.920 ;
     RECT 4.030 5.810 4.085 5.920 ;
     RECT 4.315 5.810 4.370 5.920 ;
     RECT 9.070 5.810 9.125 5.920 ;
     RECT 9.355 5.810 9.410 5.920 ;
     RECT 6.520 1.330 6.920 1.410 ;
     RECT 9.910 1.360 10.250 1.410 ;
     RECT 6.520 1.415 10.250 1.640 ;
     RECT 9.910 1.645 10.250 1.695 ;
     RECT 6.520 1.645 6.920 1.725 ;
     RECT 11.560 1.330 11.960 1.725 ;
     RECT 0.640 0.860 1.040 1.005 ;
     RECT 3.190 0.955 3.530 1.005 ;
     RECT 0.640 1.010 3.530 1.235 ;
     RECT 0.640 1.240 1.040 1.260 ;
     RECT 3.190 1.240 3.530 1.290 ;
     RECT 2.405 4.250 8.515 4.330 ;
     RECT 0.725 1.260 0.955 4.385 ;
     RECT 2.350 4.330 8.515 4.385 ;
     RECT 0.725 4.385 8.515 4.475 ;
     RECT 0.725 4.480 2.690 4.615 ;
     RECT 2.350 4.615 2.690 4.670 ;
     RECT 8.285 4.480 8.515 4.865 ;
     RECT 8.230 4.870 8.570 5.205 ;
     RECT 0.670 5.470 1.010 5.810 ;
     RECT 4.030 5.470 4.370 5.810 ;
     RECT 9.070 5.470 9.410 5.810 ;
     RECT 0.725 5.810 0.955 5.920 ;
     RECT 4.085 5.810 4.315 5.920 ;
     RECT 9.125 5.810 9.355 5.920 ;
     RECT 0.000 5.920 16.800 6.400 ;
     RECT 12.400 0.760 12.800 1.160 ;
     RECT 15.790 0.790 16.130 1.130 ;
     RECT 4.870 2.305 5.210 2.355 ;
     RECT 4.870 2.360 10.195 2.585 ;
     RECT 9.965 2.590 10.195 2.625 ;
     RECT 15.845 1.130 16.075 2.625 ;
     RECT 4.870 2.590 5.210 2.640 ;
     RECT 9.965 2.630 16.075 2.855 ;
     RECT 9.965 2.860 10.195 4.885 ;
     RECT 10.720 4.800 11.120 4.885 ;
     RECT 9.965 4.885 11.120 5.115 ;
     RECT 10.720 5.115 11.120 5.200 ;
     RECT 13.240 1.330 13.640 1.725 ;
     RECT 10.750 0.790 11.090 1.130 ;
     RECT 14.110 0.790 14.450 1.130 ;
     RECT 10.805 1.130 11.035 2.085 ;
     RECT 14.165 1.130 14.395 2.085 ;
     RECT 10.805 2.090 14.395 2.315 ;
     RECT 0.000 -0.240 16.800 0.240 ;
     RECT 2.405 0.240 2.635 0.350 ;
     RECT 7.445 0.240 7.675 0.350 ;
     RECT 9.125 0.240 9.355 0.350 ;
     RECT 2.350 0.350 2.690 0.690 ;
     RECT 7.390 0.350 7.730 0.690 ;
     RECT 9.070 0.350 9.410 0.690 ;
     RECT 14.920 1.330 15.320 1.725 ;
     RECT 4.030 0.490 4.370 0.830 ;
     RECT 1.510 2.830 1.850 2.885 ;
     RECT 4.085 0.830 4.315 2.885 ;
     RECT 5.710 2.830 6.050 2.885 ;
     RECT 1.510 2.885 6.050 3.115 ;
     RECT 1.510 3.115 1.850 3.170 ;
     RECT 5.710 3.115 6.050 3.170 ;

    LAYER Via1 ;
     RECT 6.590 1.400 6.850 1.655 ;
     RECT 11.630 1.400 11.890 1.655 ;
     RECT 0.710 0.930 0.970 1.190 ;
     RECT 0.710 6.030 0.970 6.290 ;
     RECT 2.390 6.030 2.650 6.290 ;
     RECT 4.070 6.030 4.330 6.290 ;
     RECT 5.750 6.030 6.010 6.290 ;
     RECT 7.430 6.030 7.690 6.290 ;
     RECT 9.110 6.030 9.370 6.290 ;
     RECT 10.790 6.030 11.050 6.290 ;
     RECT 12.470 6.030 12.730 6.290 ;
     RECT 14.150 6.030 14.410 6.290 ;
     RECT 15.830 6.030 16.090 6.290 ;
     RECT 12.470 0.830 12.730 1.090 ;
     RECT 10.790 4.870 11.050 5.130 ;
     RECT 13.310 1.400 13.570 1.655 ;
     RECT 0.710 -0.130 0.970 0.130 ;
     RECT 2.390 -0.130 2.650 0.130 ;
     RECT 4.070 -0.130 4.330 0.130 ;
     RECT 5.750 -0.130 6.010 0.130 ;
     RECT 7.430 -0.130 7.690 0.130 ;
     RECT 9.110 -0.130 9.370 0.130 ;
     RECT 10.790 -0.130 11.050 0.130 ;
     RECT 12.470 -0.130 12.730 0.130 ;
     RECT 14.150 -0.130 14.410 0.130 ;
     RECT 15.830 -0.130 16.090 0.130 ;
     RECT 14.990 1.400 15.250 1.655 ;

    LAYER Metal2 ;
     RECT 6.520 1.330 6.920 1.725 ;
     RECT 11.560 1.330 11.960 1.725 ;
     RECT 0.640 0.860 1.040 1.260 ;
     RECT 0.000 5.920 16.800 6.400 ;
     RECT 12.400 0.760 12.800 1.160 ;
     RECT 10.720 4.800 11.120 4.860 ;
     RECT 12.460 1.160 12.740 4.860 ;
     RECT 10.720 4.860 12.740 5.140 ;
     RECT 10.720 5.140 11.120 5.200 ;
     RECT 13.240 1.330 13.640 1.725 ;
     RECT 0.000 -0.240 16.800 0.240 ;
     RECT 14.920 1.330 15.320 1.725 ;

 END
END lsdl_nor3_x1

MACRO lsdl_nor4_x1
 CLASS CORE ;
 FOREIGN lsdl_nor4_x1 0 0 ;
 SIZE 18.48 BY 6.16 ;
 ORIGIN 0 0 ;
 SYMMETRY X Y R90 ;
 SITE unit ;
  PIN VPWR
   DIRECTION INOUT ;
   USE POWER ;
   SHAPE ABUTMENT ;
    PORT
     CLASS CORE ;
       LAYER Metal1 ;
        RECT 0.000 5.920 18.480 6.400 ;
       LAYER Metal2 ;
        RECT 0.000 5.920 18.480 6.400 ;
    END
  END VPWR

  PIN VGND
   DIRECTION INOUT ;
   USE GROUND ;
   SHAPE ABUTMENT ;
    PORT
     CLASS CORE ;
       LAYER Metal1 ;
        RECT 0.000 -0.240 18.480 0.240 ;
       LAYER Metal2 ;
        RECT 0.000 -0.240 18.480 0.240 ;
    END
  END VGND

  PIN OUT
   DIRECTION OUTPUT ;
   USE SIGNAL ;
   SHAPE ABUTMENT ;
    PORT
     CLASS CORE ;
       LAYER Metal2 ;
        RECT 9.880 4.165 10.640 4.560 ;
    END
  END OUT

  PIN A1
   DIRECTION INPUT ;
   ANTENNAGATEAREA 0.1 ;
   USE SIGNAL ;
   SHAPE ABUTMENT ;
    PORT
     CLASS CORE ;
       LAYER Metal2 ;
        RECT 3.160 1.330 3.920 1.725 ;
    END
  END A1

  PIN CLK
   DIRECTION INPUT ;
   ANTENNAGATEAREA 0.1 ;
   USE SIGNAL ;
   SHAPE ABUTMENT ;
    PORT
     CLASS CORE ;
       LAYER Metal2 ;
        RECT 7.840 1.330 8.600 1.725 ;
    END
  END CLK

  PIN A3
   DIRECTION INPUT ;
   ANTENNAGATEAREA 0.1 ;
   USE SIGNAL ;
   SHAPE ABUTMENT ;
    PORT
     CLASS CORE ;
       LAYER Metal2 ;
        RECT 4.480 1.330 5.240 1.725 ;
    END
  END A3

  PIN A2
   DIRECTION INPUT ;
   ANTENNAGATEAREA 0.1 ;
   USE SIGNAL ;
   SHAPE ABUTMENT ;
    PORT
     CLASS CORE ;
       LAYER Metal2 ;
        RECT 1.120 1.330 1.880 1.725 ;
    END
  END A2

  PIN A4
   DIRECTION INPUT ;
   ANTENNAGATEAREA 0.1 ;
   USE SIGNAL ;
   SHAPE ABUTMENT ;
    PORT
     CLASS CORE ;
       LAYER Metal2 ;
        RECT 6.160 1.330 6.920 1.725 ;
    END
  END A4

 OBS



    LAYER Metal1 ;
     RECT 9.070 0.240 9.125 0.350 ;
     RECT 9.355 0.240 9.410 0.350 ;
     RECT 10.750 0.240 10.805 0.350 ;
     RECT 11.035 0.240 11.090 0.350 ;
     RECT 15.790 0.240 15.845 0.350 ;
     RECT 16.075 0.240 16.130 0.350 ;
     RECT 9.070 5.810 9.125 5.920 ;
     RECT 9.355 5.810 9.410 5.920 ;
     RECT 14.110 5.810 14.165 5.920 ;
     RECT 14.395 5.810 14.450 5.920 ;
     RECT 15.790 5.810 15.845 5.920 ;
     RECT 16.075 5.810 16.130 5.920 ;
     RECT 8.200 1.330 8.600 1.410 ;
     RECT 11.590 1.360 11.930 1.410 ;
     RECT 8.200 1.415 11.930 1.640 ;
     RECT 11.590 1.645 11.930 1.695 ;
     RECT 8.200 1.645 8.600 1.725 ;
     RECT 1.480 1.330 1.880 1.725 ;
     RECT 14.950 0.955 15.290 1.005 ;
     RECT 17.470 0.890 17.810 1.005 ;
     RECT 14.950 1.010 17.810 1.230 ;
     RECT 14.950 1.230 17.755 1.235 ;
     RECT 14.950 1.240 15.290 1.290 ;
     RECT 9.880 4.165 10.280 4.245 ;
     RECT 17.525 1.240 17.755 4.245 ;
     RECT 9.880 4.250 17.755 4.330 ;
     RECT 9.880 4.330 17.810 4.475 ;
     RECT 9.880 4.480 10.280 4.560 ;
     RECT 17.470 4.480 17.810 4.670 ;
     RECT 9.070 5.470 9.410 5.810 ;
     RECT 14.110 5.470 14.450 5.810 ;
     RECT 15.790 5.470 16.130 5.810 ;
     RECT 9.125 5.810 9.355 5.920 ;
     RECT 14.165 5.810 14.395 5.920 ;
     RECT 15.845 5.810 16.075 5.920 ;
     RECT 0.000 5.920 18.480 6.400 ;
     RECT 2.350 0.790 2.690 1.130 ;
     RECT 5.710 0.790 6.050 1.130 ;
     RECT 5.765 1.130 5.995 2.220 ;
     RECT 13.270 2.170 13.610 2.220 ;
     RECT 5.765 2.225 13.610 2.450 ;
     RECT 13.270 2.455 13.610 2.505 ;
     RECT 2.405 1.130 2.635 4.885 ;
     RECT 5.765 2.455 5.995 4.885 ;
     RECT 7.390 4.830 7.730 4.885 ;
     RECT 2.405 4.885 7.730 5.115 ;
     RECT 7.390 5.115 7.730 5.170 ;
     RECT 3.160 1.330 3.560 1.725 ;
     RECT 0.640 0.655 1.040 1.050 ;
     RECT 4.000 0.655 4.400 1.050 ;
     RECT 7.360 0.655 7.760 1.050 ;
     RECT 0.000 -0.240 18.480 0.240 ;
     RECT 9.125 0.240 9.355 0.350 ;
     RECT 10.805 0.240 11.035 0.350 ;
     RECT 15.845 0.240 16.075 0.350 ;
     RECT 9.070 0.350 9.410 0.690 ;
     RECT 10.750 0.350 11.090 0.690 ;
     RECT 15.790 0.350 16.130 0.690 ;
     RECT 6.520 1.330 6.920 1.725 ;
     RECT 4.840 1.330 5.240 1.725 ;
     RECT 14.110 0.490 14.450 0.830 ;
     RECT 14.165 0.830 14.395 1.815 ;
     RECT 16.630 1.765 16.970 1.815 ;
     RECT 14.165 1.820 16.970 2.045 ;
     RECT 16.630 2.050 16.970 2.100 ;
     RECT 12.430 2.830 12.770 2.885 ;
     RECT 14.165 2.050 14.395 2.885 ;
     RECT 12.430 2.885 14.395 3.115 ;
     RECT 12.430 3.115 12.770 3.170 ;

    LAYER Via1 ;
     RECT 8.270 1.400 8.530 1.655 ;
     RECT 1.550 1.400 1.810 1.655 ;
     RECT 9.950 4.235 10.210 4.490 ;
     RECT 0.710 6.030 0.970 6.290 ;
     RECT 2.390 6.030 2.650 6.290 ;
     RECT 4.070 6.030 4.330 6.290 ;
     RECT 5.750 6.030 6.010 6.290 ;
     RECT 7.430 6.030 7.690 6.290 ;
     RECT 9.110 6.030 9.370 6.290 ;
     RECT 10.790 6.030 11.050 6.290 ;
     RECT 12.470 6.030 12.730 6.290 ;
     RECT 14.150 6.030 14.410 6.290 ;
     RECT 15.830 6.030 16.090 6.290 ;
     RECT 17.510 6.030 17.770 6.290 ;
     RECT 3.230 1.400 3.490 1.655 ;
     RECT 0.710 0.725 0.970 0.980 ;
     RECT 4.070 0.725 4.330 0.980 ;
     RECT 7.430 0.725 7.690 0.980 ;
     RECT 0.710 -0.130 0.970 0.130 ;
     RECT 2.390 -0.130 2.650 0.130 ;
     RECT 4.070 -0.130 4.330 0.130 ;
     RECT 5.750 -0.130 6.010 0.130 ;
     RECT 7.430 -0.130 7.690 0.130 ;
     RECT 9.110 -0.130 9.370 0.130 ;
     RECT 10.790 -0.130 11.050 0.130 ;
     RECT 12.470 -0.130 12.730 0.130 ;
     RECT 14.150 -0.130 14.410 0.130 ;
     RECT 15.830 -0.130 16.090 0.130 ;
     RECT 17.510 -0.130 17.770 0.130 ;
     RECT 6.590 1.400 6.850 1.655 ;
     RECT 4.910 1.400 5.170 1.655 ;

    LAYER Metal2 ;
     RECT 8.200 1.330 8.600 1.725 ;
     RECT 1.480 1.330 1.880 1.725 ;
     RECT 9.880 4.165 10.280 4.560 ;
     RECT 0.000 5.920 18.480 6.400 ;
     RECT 3.160 1.330 3.560 1.725 ;
     RECT 0.640 0.655 1.040 0.710 ;
     RECT 4.000 0.655 4.400 0.710 ;
     RECT 7.360 0.655 7.760 0.710 ;
     RECT 0.640 0.715 7.760 0.990 ;
     RECT 0.640 0.995 1.040 1.050 ;
     RECT 4.000 0.995 4.400 1.050 ;
     RECT 7.360 0.995 7.760 1.050 ;
     RECT 0.000 -0.240 18.480 0.240 ;
     RECT 6.520 1.330 6.920 1.725 ;
     RECT 4.840 1.330 5.240 1.725 ;

 END
END lsdl_nor4_x1

MACRO lsdl_aoi21_x1
 CLASS CORE ;
 FOREIGN lsdl_aoi21_x1 0 0 ;
 SIZE 16.8 BY 6.16 ;
 ORIGIN 0 0 ;
 SYMMETRY X Y R90 ;
 SITE unit ;
  PIN VPWR
   DIRECTION INOUT ;
   USE POWER ;
   SHAPE ABUTMENT ;
    PORT
     CLASS CORE ;
       LAYER Metal1 ;
        RECT 0.000 5.920 16.800 6.400 ;
       LAYER Metal2 ;
        RECT 0.000 5.920 16.800 6.400 ;
    END
  END VPWR

  PIN VGND
   DIRECTION INOUT ;
   USE GROUND ;
   SHAPE ABUTMENT ;
    PORT
     CLASS CORE ;
       LAYER Metal1 ;
        RECT 0.000 -0.240 16.800 0.240 ;
       LAYER Metal2 ;
        RECT 0.000 -0.240 16.800 0.240 ;
    END
  END VGND

  PIN OUT
   DIRECTION OUTPUT ;
   USE SIGNAL ;
   SHAPE ABUTMENT ;
    PORT
     CLASS CORE ;
       LAYER Metal2 ;
        RECT 0.560 0.860 1.120 1.260 ;
    END
  END OUT

  PIN A1
   DIRECTION INPUT ;
   ANTENNAGATEAREA 0.1 ;
   USE SIGNAL ;
   SHAPE ABUTMENT ;
    PORT
     CLASS CORE ;
       LAYER Metal2 ;
        RECT 13.240 1.330 14.000 1.725 ;
    END
  END A1

  PIN CLK
   DIRECTION INPUT ;
   ANTENNAGATEAREA 0.1 ;
   USE SIGNAL ;
   SHAPE ABUTMENT ;
    PORT
     CLASS CORE ;
       LAYER Metal2 ;
        RECT 6.160 1.330 6.920 1.725 ;
    END
  END CLK

  PIN A2
   DIRECTION INPUT ;
   ANTENNAGATEAREA 0.1 ;
   USE SIGNAL ;
   SHAPE ABUTMENT ;
    PORT
     CLASS CORE ;
       LAYER Metal2 ;
        RECT 14.560 1.330 15.320 1.725 ;
    END
  END A2

  PIN B
   DIRECTION INPUT ;
   ANTENNAGATEAREA 0.1 ;
   USE SIGNAL ;
   SHAPE ABUTMENT ;
    PORT
     CLASS CORE ;
       LAYER Metal2 ;
        RECT 11.560 1.330 12.320 1.725 ;
    END
  END B

 OBS



    LAYER Metal1 ;
     RECT 2.350 0.240 2.405 0.350 ;
     RECT 2.635 0.240 2.690 0.350 ;
     RECT 7.390 0.240 7.445 0.350 ;
     RECT 7.675 0.240 7.730 0.350 ;
     RECT 9.070 0.240 9.125 0.350 ;
     RECT 9.355 0.240 9.410 0.350 ;
     RECT 0.670 5.810 0.725 5.920 ;
     RECT 0.955 5.810 1.010 5.920 ;
     RECT 4.030 5.810 4.085 5.920 ;
     RECT 4.315 5.810 4.370 5.920 ;
     RECT 9.070 5.810 9.125 5.920 ;
     RECT 9.355 5.810 9.410 5.920 ;
     RECT 11.560 1.330 11.960 1.725 ;
     RECT 6.520 1.330 6.920 1.410 ;
     RECT 9.910 1.360 10.250 1.410 ;
     RECT 6.520 1.415 10.250 1.640 ;
     RECT 9.910 1.645 10.250 1.695 ;
     RECT 6.520 1.645 6.920 1.725 ;
     RECT 14.920 1.330 15.320 1.725 ;
     RECT 0.640 0.860 1.040 1.005 ;
     RECT 3.190 0.955 3.530 1.005 ;
     RECT 0.640 1.010 3.530 1.235 ;
     RECT 0.640 1.240 1.040 1.260 ;
     RECT 3.190 1.240 3.530 1.290 ;
     RECT 2.405 4.250 8.515 4.330 ;
     RECT 0.725 1.260 0.955 4.385 ;
     RECT 2.350 4.330 8.515 4.385 ;
     RECT 0.725 4.385 8.515 4.475 ;
     RECT 0.725 4.480 2.690 4.615 ;
     RECT 2.350 4.615 2.690 4.670 ;
     RECT 8.285 4.480 8.515 4.865 ;
     RECT 8.230 4.870 8.570 5.205 ;
     RECT 0.670 5.470 1.010 5.810 ;
     RECT 4.030 5.470 4.370 5.810 ;
     RECT 9.070 5.470 9.410 5.810 ;
     RECT 0.725 5.810 0.955 5.920 ;
     RECT 4.085 5.810 4.315 5.920 ;
     RECT 9.125 5.810 9.355 5.920 ;
     RECT 0.000 5.920 16.800 6.400 ;
     RECT 12.430 0.790 12.770 1.130 ;
     RECT 4.870 2.170 5.210 2.220 ;
     RECT 12.485 1.130 12.715 2.220 ;
     RECT 4.870 2.225 12.715 2.450 ;
     RECT 4.870 2.455 5.210 2.505 ;
     RECT 10.750 4.830 11.090 4.885 ;
     RECT 12.485 2.455 12.715 4.885 ;
     RECT 10.750 4.885 12.715 5.115 ;
     RECT 10.750 5.115 11.090 5.170 ;
     RECT 13.240 1.330 13.640 1.725 ;
     RECT 10.720 0.655 11.120 1.050 ;
     RECT 15.760 0.655 16.160 1.050 ;
     RECT 0.000 -0.240 16.800 0.240 ;
     RECT 2.405 0.240 2.635 0.350 ;
     RECT 7.445 0.240 7.675 0.350 ;
     RECT 9.125 0.240 9.355 0.350 ;
     RECT 2.350 0.350 2.690 0.690 ;
     RECT 7.390 0.350 7.730 0.690 ;
     RECT 9.070 0.350 9.410 0.690 ;
     RECT 4.030 0.490 4.370 0.830 ;
     RECT 1.510 2.830 1.850 2.885 ;
     RECT 4.085 0.830 4.315 2.885 ;
     RECT 5.710 2.830 6.050 2.885 ;
     RECT 1.510 2.885 6.050 3.115 ;
     RECT 1.510 3.115 1.850 3.170 ;
     RECT 5.710 3.115 6.050 3.170 ;

    LAYER Via1 ;
     RECT 11.630 1.400 11.890 1.655 ;
     RECT 6.590 1.400 6.850 1.655 ;
     RECT 14.990 1.400 15.250 1.655 ;
     RECT 0.710 0.930 0.970 1.190 ;
     RECT 0.710 6.030 0.970 6.290 ;
     RECT 2.390 6.030 2.650 6.290 ;
     RECT 4.070 6.030 4.330 6.290 ;
     RECT 5.750 6.030 6.010 6.290 ;
     RECT 7.430 6.030 7.690 6.290 ;
     RECT 9.110 6.030 9.370 6.290 ;
     RECT 10.790 6.030 11.050 6.290 ;
     RECT 12.470 6.030 12.730 6.290 ;
     RECT 14.150 6.030 14.410 6.290 ;
     RECT 15.830 6.030 16.090 6.290 ;
     RECT 13.310 1.400 13.570 1.655 ;
     RECT 10.790 0.725 11.050 0.980 ;
     RECT 15.830 0.725 16.090 0.980 ;
     RECT 0.710 -0.130 0.970 0.130 ;
     RECT 2.390 -0.130 2.650 0.130 ;
     RECT 4.070 -0.130 4.330 0.130 ;
     RECT 5.750 -0.130 6.010 0.130 ;
     RECT 7.430 -0.130 7.690 0.130 ;
     RECT 9.110 -0.130 9.370 0.130 ;
     RECT 10.790 -0.130 11.050 0.130 ;
     RECT 12.470 -0.130 12.730 0.130 ;
     RECT 14.150 -0.130 14.410 0.130 ;
     RECT 15.830 -0.130 16.090 0.130 ;

    LAYER Metal2 ;
     RECT 11.560 1.330 11.960 1.725 ;
     RECT 6.520 1.330 6.920 1.725 ;
     RECT 14.920 1.330 15.320 1.725 ;
     RECT 0.640 0.860 1.040 1.260 ;
     RECT 0.000 5.920 16.800 6.400 ;
     RECT 13.240 1.330 13.640 1.725 ;
     RECT 10.720 0.655 11.120 0.710 ;
     RECT 15.760 0.655 16.160 0.710 ;
     RECT 10.720 0.715 16.160 0.990 ;
     RECT 10.720 0.995 11.120 1.050 ;
     RECT 15.760 0.995 16.160 1.050 ;
     RECT 0.000 -0.240 16.800 0.240 ;

 END
END lsdl_aoi21_x1

MACRO lsdl_aoi22_x1
 CLASS CORE ;
 FOREIGN lsdl_aoi22_x1 0 0 ;
 SIZE 18.48 BY 6.16 ;
 ORIGIN 0 0 ;
 SYMMETRY X Y R90 ;
 SITE unit ;
  PIN VPWR
   DIRECTION INOUT ;
   USE POWER ;
   SHAPE ABUTMENT ;
    PORT
     CLASS CORE ;
       LAYER Metal1 ;
        RECT 0.000 5.920 18.480 6.400 ;
       LAYER Metal2 ;
        RECT 0.000 5.920 18.480 6.400 ;
    END
  END VPWR

  PIN VGND
   DIRECTION INOUT ;
   USE GROUND ;
   SHAPE ABUTMENT ;
    PORT
     CLASS CORE ;
       LAYER Metal1 ;
        RECT 0.000 -0.240 18.480 0.240 ;
       LAYER Metal2 ;
        RECT 0.000 -0.240 18.480 0.240 ;
    END
  END VGND

  PIN OUT
   DIRECTION OUTPUT ;
   USE SIGNAL ;
   SHAPE ABUTMENT ;
    PORT
     CLASS CORE ;
       LAYER Metal2 ;
        RECT 0.560 0.860 1.120 1.260 ;
    END
  END OUT

  PIN B1
   DIRECTION INPUT ;
   ANTENNAGATEAREA 0.1 ;
   USE SIGNAL ;
   SHAPE ABUTMENT ;
    PORT
     CLASS CORE ;
       LAYER Metal2 ;
        RECT 13.240 1.330 14.000 1.725 ;
    END
  END B1

  PIN B2
   DIRECTION INPUT ;
   ANTENNAGATEAREA 0.1 ;
   USE SIGNAL ;
   SHAPE ABUTMENT ;
    PORT
     CLASS CORE ;
       LAYER Metal2 ;
        RECT 11.560 1.330 12.320 1.725 ;
    END
  END B2

  PIN CLK
   DIRECTION INPUT ;
   ANTENNAGATEAREA 0.1 ;
   USE SIGNAL ;
   SHAPE ABUTMENT ;
    PORT
     CLASS CORE ;
       LAYER Metal2 ;
        RECT 6.160 1.330 6.920 1.725 ;
    END
  END CLK

  PIN A1
   DIRECTION INPUT ;
   ANTENNAGATEAREA 0.1 ;
   USE SIGNAL ;
   SHAPE ABUTMENT ;
    PORT
     CLASS CORE ;
       LAYER Metal2 ;
        RECT 14.920 1.330 15.680 1.725 ;
    END
  END A1

  PIN A2
   DIRECTION INPUT ;
   ANTENNAGATEAREA 0.1 ;
   USE SIGNAL ;
   SHAPE ABUTMENT ;
    PORT
     CLASS CORE ;
       LAYER Metal2 ;
        RECT 16.240 1.330 17.000 1.725 ;
    END
  END A2

 OBS



    LAYER Metal1 ;
     RECT 2.350 0.240 2.405 0.350 ;
     RECT 2.635 0.240 2.690 0.350 ;
     RECT 7.390 0.240 7.445 0.350 ;
     RECT 7.675 0.240 7.730 0.350 ;
     RECT 9.070 0.240 9.125 0.350 ;
     RECT 9.355 0.240 9.410 0.350 ;
     RECT 0.670 5.810 0.725 5.920 ;
     RECT 0.955 5.810 1.010 5.920 ;
     RECT 4.030 5.810 4.085 5.920 ;
     RECT 4.315 5.810 4.370 5.920 ;
     RECT 9.070 5.810 9.125 5.920 ;
     RECT 9.355 5.810 9.410 5.920 ;
     RECT 11.560 1.330 11.960 1.725 ;
     RECT 6.520 1.330 6.920 1.410 ;
     RECT 9.910 1.360 10.250 1.410 ;
     RECT 6.520 1.415 10.250 1.640 ;
     RECT 9.910 1.645 10.250 1.695 ;
     RECT 6.520 1.645 6.920 1.725 ;
     RECT 16.600 1.330 17.000 1.725 ;
     RECT 0.640 0.860 1.040 1.005 ;
     RECT 3.190 0.955 3.530 1.005 ;
     RECT 0.640 1.010 3.530 1.235 ;
     RECT 0.640 1.240 1.040 1.260 ;
     RECT 3.190 1.240 3.530 1.290 ;
     RECT 2.405 4.250 8.515 4.330 ;
     RECT 0.725 1.260 0.955 4.385 ;
     RECT 2.350 4.330 8.515 4.385 ;
     RECT 0.725 4.385 8.515 4.475 ;
     RECT 0.725 4.480 2.690 4.615 ;
     RECT 2.350 4.615 2.690 4.670 ;
     RECT 8.285 4.480 8.515 4.865 ;
     RECT 8.230 4.870 8.570 5.205 ;
     RECT 0.670 5.470 1.010 5.810 ;
     RECT 4.030 5.470 4.370 5.810 ;
     RECT 9.070 5.470 9.410 5.810 ;
     RECT 0.725 5.810 0.955 5.920 ;
     RECT 4.085 5.810 4.315 5.920 ;
     RECT 9.125 5.810 9.355 5.920 ;
     RECT 0.000 5.920 18.480 6.400 ;
     RECT 14.110 0.790 14.450 1.130 ;
     RECT 4.870 2.305 5.210 2.355 ;
     RECT 14.165 1.130 14.395 2.355 ;
     RECT 4.870 2.360 14.395 2.585 ;
     RECT 4.870 2.590 5.210 2.640 ;
     RECT 10.750 4.830 11.090 4.885 ;
     RECT 14.165 2.590 14.395 4.885 ;
     RECT 10.750 4.885 14.395 5.115 ;
     RECT 10.750 5.115 11.090 5.170 ;
     RECT 14.920 1.330 15.320 1.725 ;
     RECT 10.720 0.655 11.120 1.050 ;
     RECT 17.440 0.655 17.840 1.050 ;
     RECT 0.000 -0.240 18.480 0.240 ;
     RECT 2.405 0.240 2.635 0.350 ;
     RECT 7.445 0.240 7.675 0.350 ;
     RECT 9.125 0.240 9.355 0.350 ;
     RECT 2.350 0.350 2.690 0.690 ;
     RECT 7.390 0.350 7.730 0.690 ;
     RECT 9.070 0.350 9.410 0.690 ;
     RECT 13.240 1.330 13.640 1.725 ;
     RECT 4.030 0.490 4.370 0.830 ;
     RECT 1.510 2.830 1.850 2.885 ;
     RECT 4.085 0.830 4.315 2.885 ;
     RECT 5.710 2.830 6.050 2.885 ;
     RECT 1.510 2.885 6.050 3.115 ;
     RECT 1.510 3.115 1.850 3.170 ;
     RECT 5.710 3.115 6.050 3.170 ;

    LAYER Via1 ;
     RECT 11.630 1.400 11.890 1.655 ;
     RECT 6.590 1.400 6.850 1.655 ;
     RECT 16.670 1.400 16.930 1.655 ;
     RECT 0.710 0.930 0.970 1.190 ;
     RECT 0.710 6.030 0.970 6.290 ;
     RECT 2.390 6.030 2.650 6.290 ;
     RECT 4.070 6.030 4.330 6.290 ;
     RECT 5.750 6.030 6.010 6.290 ;
     RECT 7.430 6.030 7.690 6.290 ;
     RECT 9.110 6.030 9.370 6.290 ;
     RECT 10.790 6.030 11.050 6.290 ;
     RECT 12.470 6.030 12.730 6.290 ;
     RECT 14.150 6.030 14.410 6.290 ;
     RECT 15.830 6.030 16.090 6.290 ;
     RECT 17.510 6.030 17.770 6.290 ;
     RECT 14.990 1.400 15.250 1.655 ;
     RECT 10.790 0.725 11.050 0.980 ;
     RECT 17.510 0.725 17.770 0.980 ;
     RECT 0.710 -0.130 0.970 0.130 ;
     RECT 2.390 -0.130 2.650 0.130 ;
     RECT 4.070 -0.130 4.330 0.130 ;
     RECT 5.750 -0.130 6.010 0.130 ;
     RECT 7.430 -0.130 7.690 0.130 ;
     RECT 9.110 -0.130 9.370 0.130 ;
     RECT 10.790 -0.130 11.050 0.130 ;
     RECT 12.470 -0.130 12.730 0.130 ;
     RECT 14.150 -0.130 14.410 0.130 ;
     RECT 15.830 -0.130 16.090 0.130 ;
     RECT 17.510 -0.130 17.770 0.130 ;
     RECT 13.310 1.400 13.570 1.655 ;

    LAYER Metal2 ;
     RECT 11.560 1.330 11.960 1.725 ;
     RECT 6.520 1.330 6.920 1.725 ;
     RECT 16.600 1.330 17.000 1.725 ;
     RECT 0.640 0.860 1.040 1.260 ;
     RECT 0.000 5.920 18.480 6.400 ;
     RECT 14.920 1.330 15.320 1.725 ;
     RECT 10.720 0.655 11.120 0.710 ;
     RECT 17.440 0.655 17.840 0.710 ;
     RECT 10.720 0.715 17.840 0.990 ;
     RECT 10.720 0.995 11.120 1.050 ;
     RECT 17.440 0.995 17.840 1.050 ;
     RECT 0.000 -0.240 18.480 0.240 ;
     RECT 13.240 1.330 13.640 1.725 ;

 END
END lsdl_aoi22_x1

END LIBRARY
